VERSION 5.8 ;
BUSBITCHARS "[]" ;
DIVIDERCHAR "/" ;
UNITS
    DATABASE MICRONS 1000 ;
END UNITS

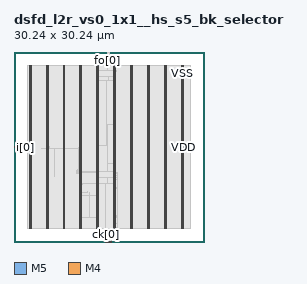
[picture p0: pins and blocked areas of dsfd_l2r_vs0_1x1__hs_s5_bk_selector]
MACRO dsfd_l2r_vs0_1x1__hs_s5_bk_selector
  FOREIGN dsfd_l2r_vs0_1x1__hs_s5_bk_selector 0 0 ;
  CLASS BLOCK ;
  SIZE 30.24 BY 30.24 ;
  PIN ck[0]
    DIRECTION INPUT ;
    USE SIGNAL ;
    PORT
      LAYER M5 ;
        RECT  14.64 0 14.664 0.084 ;
    END
  END ck[0]
  PIN cks[0]
    DIRECTION INPUT ;
    USE SIGNAL ;
    PORT
      LAYER M5 ;
        RECT  14.832 0 14.856 0.084 ;
    END
  END cks[0]
  PIN fo[0]
    DIRECTION OUTPUT ;
    USE SIGNAL ;
    PORT
      LAYER M5 ;
        RECT  14.928 30.156 14.952 30.24 ;
    END
  END fo[0]
  PIN i[0]
    DIRECTION INPUT ;
    USE SIGNAL ;
    PORT
      LAYER M4 ;
        RECT  0 15.072 0.084 15.096 ;
    END
  END i[0]
  PIN i[1]
    DIRECTION INPUT ;
    USE SIGNAL ;
    PORT
      LAYER M4 ;
        RECT  0 15.12 0.084 15.144 ;
    END
  END i[1]
  PIN od[0]
    DIRECTION OUTPUT ;
    USE SIGNAL ;
    PORT
      LAYER M5 ;
        RECT  15.12 30.156 15.144 30.24 ;
    END
  END od[0]
  PIN od[1]
    DIRECTION OUTPUT ;
    USE SIGNAL ;
    PORT
      LAYER M5 ;
        RECT  15.168 30.156 15.192 30.24 ;
    END
  END od[1]
  PIN od[2]
    DIRECTION OUTPUT ;
    USE SIGNAL ;
    PORT
      LAYER M5 ;
        RECT  15.216 30.156 15.24 30.24 ;
    END
  END od[2]
  PIN rs[0]
    DIRECTION INPUT ;
    USE SIGNAL ;
    PORT
      LAYER M5 ;
        RECT  15.024 0 15.048 0.084 ;
    END
  END rs[0]
  PIN rss[0]
    DIRECTION INPUT ;
    USE SIGNAL ;
    PORT
      LAYER M5 ;
        RECT  15.216 0 15.24 0.084 ;
    END
  END rss[0]
  PIN xf[0]
    DIRECTION INPUT ;
    USE SIGNAL ;
    PORT
      LAYER M5 ;
        RECT  15.408 0 15.432 0.084 ;
    END
  END xf[0]
  PIN xf[1]
    DIRECTION INPUT ;
    USE SIGNAL ;
    PORT
      LAYER M5 ;
        RECT  15.456 0 15.48 0.084 ;
    END
  END xf[1]
  PIN xf[2]
    DIRECTION INPUT ;
    USE SIGNAL ;
    PORT
      LAYER M5 ;
        RECT  15.504 0 15.528 0.084 ;
    END
  END xf[2]
  PIN xf[3]
    DIRECTION INPUT ;
    USE SIGNAL ;
    PORT
      LAYER M5 ;
        RECT  15.552 0 15.576 0.084 ;
    END
  END xf[3]
  PIN VDD
    DIRECTION INOUT ;
    USE POWER ;
    PORT
      LAYER M5 ;
        RECT  26.892 2.151 27.012 28.089 ;
        RECT  24.192 2.151 24.312 28.089 ;
        RECT  21.492 2.151 21.612 28.089 ;
        RECT  18.792 2.151 18.912 28.089 ;
        RECT  16.092 2.151 16.212 28.089 ;
        RECT  13.392 2.151 13.512 28.089 ;
        RECT  10.692 2.151 10.812 28.089 ;
        RECT  7.992 2.151 8.112 28.089 ;
        RECT  5.292 2.151 5.412 28.089 ;
        RECT  2.592 2.151 2.712 28.089 ;
    END
  END VDD
  PIN VSS
    DIRECTION INOUT ;
    USE GROUND ;
    PORT
      LAYER M5 ;
        RECT  26.7 2.137 26.82 28.103 ;
        RECT  24 2.137 24.12 28.103 ;
        RECT  21.3 2.137 21.42 28.103 ;
        RECT  18.6 2.137 18.72 28.103 ;
        RECT  15.9 2.137 16.02 28.103 ;
        RECT  13.2 2.137 13.32 28.103 ;
        RECT  10.5 2.137 10.62 28.103 ;
        RECT  7.8 2.137 7.92 28.103 ;
        RECT  5.1 2.137 5.22 28.103 ;
        RECT  2.4 2.137 2.52 28.103 ;
    END
  END VSS
  # OT_OBS_CLOSED layer=M5 d_um=1.536 added=11
  OBS
    LAYER RVTN ;
     RECT  2.16 2.16 28.08 2.295 ;
     RECT  2.16 2.565 28.08 2.835 ;
     RECT  2.16 3.105 28.08 3.375 ;
     RECT  2.16 3.645 28.08 3.915 ;
     RECT  2.16 4.185 28.08 4.455 ;
     RECT  2.16 4.725 28.08 4.995 ;
     RECT  2.16 5.265 28.08 5.535 ;
     RECT  2.16 5.805 28.08 6.075 ;
     RECT  2.16 6.345 28.08 6.615 ;
     RECT  2.16 6.885 28.08 7.155 ;
     RECT  2.16 7.425 28.08 7.695 ;
     RECT  2.16 7.965 28.08 8.235 ;
     RECT  2.16 8.505 28.08 8.775 ;
     RECT  2.16 9.045 28.08 9.315 ;
     RECT  2.16 9.585 28.08 9.855 ;
     RECT  2.16 10.125 28.08 10.395 ;
     RECT  2.16 10.665 28.08 10.935 ;
     RECT  2.16 11.205 28.08 11.475 ;
     RECT  2.16 11.745 28.08 12.015 ;
     RECT  2.16 12.285 28.08 12.555 ;
     RECT  2.16 12.825 28.08 13.095 ;
     RECT  2.16 13.365 28.08 13.635 ;
     RECT  2.16 13.905 28.08 14.175 ;
     RECT  2.16 14.445 28.08 14.715 ;
     RECT  2.16 14.985 28.08 15.255 ;
     RECT  2.16 15.525 28.08 15.795 ;
     RECT  2.16 16.065 28.08 16.335 ;
     RECT  2.16 16.605 28.08 16.875 ;
     RECT  2.16 17.145 28.08 17.415 ;
     RECT  2.16 17.685 28.08 17.955 ;
     RECT  2.16 18.225 28.08 18.495 ;
     RECT  2.16 18.765 28.08 19.035 ;
     RECT  2.16 19.305 28.08 19.575 ;
     RECT  2.16 19.845 28.08 20.115 ;
     RECT  2.16 20.385 28.08 20.655 ;
     RECT  2.16 20.925 28.08 21.195 ;
     RECT  2.16 21.465 28.08 21.735 ;
     RECT  2.16 22.005 28.08 22.275 ;
     RECT  2.16 22.545 28.08 22.815 ;
     RECT  2.16 23.085 28.08 23.355 ;
     RECT  2.16 23.625 28.08 23.895 ;
     RECT  2.16 24.165 28.08 24.435 ;
     RECT  2.16 24.705 28.08 24.975 ;
     RECT  2.16 25.245 28.08 25.515 ;
     RECT  2.16 25.785 28.08 26.055 ;
     RECT  2.16 26.325 28.08 26.595 ;
     RECT  2.16 26.865 28.08 27.135 ;
     RECT  2.16 27.405 28.08 27.675 ;
     RECT  2.16 27.945 28.08 28.08 ;
    LAYER RVTP ;
     RECT  2.16 2.295 28.08 2.565 ;
     RECT  2.16 2.835 28.08 3.105 ;
     RECT  2.16 3.375 28.08 3.645 ;
     RECT  2.16 3.915 28.08 4.185 ;
     RECT  2.16 4.455 28.08 4.725 ;
     RECT  2.16 4.995 28.08 5.265 ;
     RECT  2.16 5.535 28.08 5.805 ;
     RECT  2.16 6.075 28.08 6.345 ;
     RECT  2.16 6.615 28.08 6.885 ;
     RECT  2.16 7.155 28.08 7.425 ;
     RECT  2.16 7.695 28.08 7.965 ;
     RECT  2.16 8.235 28.08 8.505 ;
     RECT  2.16 8.775 28.08 9.045 ;
     RECT  2.16 9.315 28.08 9.585 ;
     RECT  2.16 9.855 28.08 10.125 ;
     RECT  2.16 10.395 28.08 10.665 ;
     RECT  2.16 10.935 28.08 11.205 ;
     RECT  2.16 11.475 28.08 11.745 ;
     RECT  2.16 12.015 28.08 12.285 ;
     RECT  2.16 12.555 28.08 12.825 ;
     RECT  2.16 13.095 28.08 13.365 ;
     RECT  2.16 13.635 28.08 13.905 ;
     RECT  2.16 14.175 28.08 14.445 ;
     RECT  2.16 14.715 28.08 14.985 ;
     RECT  2.16 15.255 28.08 15.525 ;
     RECT  2.16 15.795 28.08 16.065 ;
     RECT  2.16 16.335 28.08 16.605 ;
     RECT  2.16 16.875 28.08 17.145 ;
     RECT  2.16 17.415 28.08 17.685 ;
     RECT  2.16 17.955 28.08 18.225 ;
     RECT  2.16 18.495 28.08 18.765 ;
     RECT  2.16 19.035 28.08 19.305 ;
     RECT  2.16 19.575 28.08 19.845 ;
     RECT  2.16 20.115 28.08 20.385 ;
     RECT  2.16 20.655 28.08 20.925 ;
     RECT  2.16 21.195 28.08 21.465 ;
     RECT  2.16 21.735 28.08 22.005 ;
     RECT  2.16 22.275 28.08 22.545 ;
     RECT  2.16 22.815 28.08 23.085 ;
     RECT  2.16 23.355 28.08 23.625 ;
     RECT  2.16 23.895 28.08 24.165 ;
     RECT  2.16 24.435 28.08 24.705 ;
     RECT  2.16 24.975 28.08 25.245 ;
     RECT  2.16 25.515 28.08 25.785 ;
     RECT  2.16 26.055 28.08 26.325 ;
     RECT  2.16 26.595 28.08 26.865 ;
     RECT  2.16 27.135 28.08 27.405 ;
     RECT  2.16 27.675 28.08 27.945 ;
    LAYER M1 ;
     RECT  2.16 2.151 28.08 28.089 ;
    LAYER M2 ;
     RECT  2.16 2.151 28.08 28.089 ;
    LAYER M3 ;
     RECT  15.3 0.139 15.318 1.723 ;
     RECT  15.3 1.723 15.498 1.771 ;
     RECT  15.3 1.771 15.75 2.143 ;
     RECT  15.3 2.143 16.005 2.263 ;
     RECT  2.415 2.143 2.505 2.413 ;
     RECT  5.115 2.143 5.205 2.413 ;
     RECT  7.815 2.143 7.905 2.413 ;
     RECT  10.515 2.143 10.605 2.413 ;
     RECT  13.215 2.143 13.305 2.413 ;
     RECT  18.615 2.143 18.705 2.413 ;
     RECT  21.315 2.143 21.405 2.413 ;
     RECT  24.015 2.143 24.105 2.413 ;
     RECT  26.715 2.143 26.805 2.413 ;
     RECT  15.3 2.263 16.398 2.911 ;
     RECT  15.048 2.911 16.398 3.839 ;
     RECT  14.508 3.847 14.526 3.917 ;
     RECT  15.264 3.839 16.398 3.991 ;
     RECT  15.264 3.991 16.542 4.145 ;
     RECT  11.952 7.435 11.97 7.889 ;
     RECT  11.736 7.915 11.754 7.961 ;
     RECT  15.444 4.145 16.542 8.539 ;
     RECT  14.976 8.539 16.542 8.735 ;
     RECT  10.515 2.413 10.797 9.115 ;
     RECT  10.515 9.115 10.854 9.293 ;
     RECT  13.215 2.413 13.497 9.895 ;
     RECT  15.012 8.735 16.542 9.895 ;
     RECT  13.215 9.895 14.094 9.931 ;
     RECT  13.215 9.931 14.238 10.021 ;
     RECT  14.976 9.895 16.542 10.021 ;
     RECT  13.215 10.021 16.542 10.301 ;
     RECT  14.436 10.301 16.542 10.625 ;
     RECT  10.515 9.293 10.797 10.843 ;
     RECT  14.724 10.625 16.542 10.895 ;
     RECT  15.3 10.895 16.542 11.039 ;
     RECT  5.115 2.413 5.397 11.137 ;
     RECT  9.972 10.843 10.797 11.137 ;
     RECT  9.972 11.137 10.854 11.273 ;
     RECT  9.972 11.273 10.797 11.399 ;
     RECT  10.224 11.399 10.797 11.705 ;
     RECT  15.3 11.039 16.197 12.523 ;
     RECT  15.192 12.523 16.197 13.531 ;
     RECT  15.048 13.531 16.197 14.377 ;
     RECT  6.48 10.471 6.498 14.909 ;
     RECT  5.115 11.137 5.454 14.917 ;
     RECT  4.464 14.917 5.562 14.957 ;
     RECT  2.415 2.413 2.697 15.025 ;
     RECT  5.115 14.957 5.562 15.061 ;
     RECT  2.304 15.025 2.697 15.115 ;
     RECT  5.115 15.061 5.706 15.179 ;
     RECT  2.232 15.115 2.697 15.215 ;
     RECT  14.616 14.377 16.197 15.323 ;
     RECT  14.76 15.323 16.197 15.341 ;
     RECT  15.012 15.341 16.197 15.485 ;
     RECT  15.048 15.485 16.197 18.379 ;
     RECT  14.904 18.379 16.197 18.571 ;
     RECT  14.724 18.571 16.197 18.797 ;
     RECT  15.048 18.797 16.197 18.833 ;
     RECT  15.12 18.833 16.197 20.539 ;
     RECT  14.76 20.539 16.197 20.849 ;
     RECT  15.048 20.849 16.197 23.371 ;
     RECT  14.832 23.371 16.197 23.549 ;
     RECT  15.012 23.549 16.197 23.741 ;
     RECT  15.048 23.741 16.197 25.675 ;
     RECT  14.724 25.675 16.197 26.015 ;
     RECT  14.94 26.015 16.197 26.779 ;
     RECT  14.76 26.779 16.197 27.211 ;
     RECT  14.76 27.211 16.254 27.329 ;
     RECT  14.76 27.329 16.197 27.365 ;
     RECT  2.415 15.215 2.697 27.827 ;
     RECT  5.115 15.179 5.397 27.827 ;
     RECT  7.815 2.413 8.097 27.827 ;
     RECT  10.515 11.705 10.797 27.827 ;
     RECT  13.215 10.301 13.497 27.827 ;
     RECT  14.868 27.365 16.197 27.827 ;
     RECT  18.615 2.413 18.897 27.827 ;
     RECT  21.315 2.413 21.597 27.827 ;
     RECT  24.015 2.413 24.297 27.827 ;
     RECT  26.715 2.413 26.997 27.827 ;
     RECT  14.868 27.827 16.038 27.869 ;
     RECT  14.868 27.869 16.005 27.905 ;
     RECT  2.415 27.827 2.505 28.097 ;
     RECT  5.115 27.827 5.205 28.097 ;
     RECT  7.815 27.827 7.905 28.097 ;
     RECT  10.515 27.827 10.605 28.097 ;
     RECT  13.215 27.827 13.305 28.097 ;
     RECT  15.084 27.905 16.005 28.097 ;
     RECT  18.615 27.827 18.705 28.097 ;
     RECT  21.315 27.827 21.405 28.097 ;
     RECT  24.015 27.827 24.105 28.097 ;
     RECT  26.715 27.827 26.805 28.097 ;
     RECT  15.084 28.097 15.39 28.493 ;
     RECT  15.084 28.493 15.102 29.069 ;
    LAYER M4 ;
     RECT  0.06 15.072 2.408 15.144 ;
     RECT  2.408 2.148 2.512 28.092 ;
     RECT  2.512 2.418 2.704 27.822 ;
     RECT  4.453 14.928 5.108 14.952 ;
     RECT  5.108 2.148 5.212 28.092 ;
     RECT  5.212 2.418 5.404 27.822 ;
     RECT  5.404 14.928 7.808 14.952 ;
     RECT  7.808 2.148 7.912 28.092 ;
     RECT  7.912 2.418 8.104 27.822 ;
     RECT  9.961 10.848 10.172 10.872 ;
     RECT  10.357 7.92 10.508 7.944 ;
     RECT  10.357 9.408 10.508 9.432 ;
     RECT  10.172 10.848 10.508 11.592 ;
     RECT  8.104 14.928 10.508 14.952 ;
     RECT  10.508 2.148 10.612 28.092 ;
     RECT  10.612 2.418 10.804 27.822 ;
     RECT  10.804 9.12 10.865 9.288 ;
     RECT  10.804 7.92 11.765 7.944 ;
     RECT  11.941 7.44 12.025 7.464 ;
     RECT  11.941 3.888 13.208 3.912 ;
     RECT  10.865 9.264 13.208 9.288 ;
     RECT  10.804 11.136 13.208 11.16 ;
     RECT  13.208 2.148 13.312 28.092 ;
     RECT  13.312 2.418 13.504 27.822 ;
     RECT  13.504 10.272 14.243 11.16 ;
     RECT  14.243 10.272 14.465 10.296 ;
     RECT  13.504 9.264 14.675 9.288 ;
     RECT  14.713 18.768 14.725 18.792 ;
     RECT  14.713 25.68 14.797 25.704 ;
     RECT  14.725 15.312 14.812 15.336 ;
     RECT  14.749 20.544 14.867 20.568 ;
     RECT  14.749 26.784 14.885 26.808 ;
     RECT  14.885 26.784 14.924 27.336 ;
     RECT  14.725 18.384 14.933 18.792 ;
     RECT  14.821 23.376 14.957 23.4 ;
     RECT  15.073 29.04 15.109 29.064 ;
     RECT  15.109 28.464 15.173 29.064 ;
     RECT  15.173 28.416 15.203 29.064 ;
     RECT  15.203 28.416 15.401 28.488 ;
     RECT  15.289 0.144 15.491 0.168 ;
     RECT  15.397 1.728 15.493 1.752 ;
     RECT  15.493 1.728 15.509 1.8 ;
     RECT  15.509 1.776 15.533 1.8 ;
     RECT  15.533 1.776 15.761 1.896 ;
     RECT  13.504 3.888 15.908 3.912 ;
     RECT  14.965 8.544 15.908 8.568 ;
     RECT  15.181 12.528 15.908 12.552 ;
     RECT  14.933 18.768 15.908 18.792 ;
     RECT  14.917 20.688 15.908 20.856 ;
     RECT  14.957 23.376 15.908 23.736 ;
     RECT  14.924 26.256 15.908 27.336 ;
     RECT  15.908 2.148 16.012 28.092 ;
     RECT  16.012 2.418 16.204 27.822 ;
     RECT  18.608 2.148 18.712 28.092 ;
     RECT  18.712 2.418 18.904 27.822 ;
     RECT  21.308 2.148 21.412 28.092 ;
     RECT  21.412 2.418 21.604 27.822 ;
     RECT  24.008 2.148 24.112 28.092 ;
     RECT  24.112 2.418 24.304 27.822 ;
     RECT  26.708 2.148 26.812 28.092 ;
     RECT  26.812 2.418 27.004 27.822 ;
    LAYER M5 ;
     RECT  14.64 0.016 15.576 2.137 ;
     RECT  2.4 2.137 2.52 2.151 ;
     RECT  5.1 2.137 5.22 2.151 ;
     RECT  7.8 2.137 7.92 2.151 ;
     RECT  10.5 2.137 10.62 2.151 ;
     RECT  13.2 2.137 13.32 2.151 ;
     RECT  14.64 2.137 16.02 2.151 ;
     RECT  18.6 2.137 18.72 2.151 ;
     RECT  21.3 2.137 21.42 2.151 ;
     RECT  24 2.137 24.12 2.151 ;
     RECT  26.7 2.137 26.82 2.151 ;
     RECT  11.952 3.877 11.976 7.475 ;
     RECT  10.5 2.151 10.812 7.909 ;
     RECT  14.64 2.151 16.212 9.299 ;
     RECT  13.2 2.151 13.512 10.261 ;
     RECT  14.832 9.299 16.212 10.261 ;
     RECT  10.368 7.909 10.812 11.125 ;
     RECT  13.2 10.261 16.212 11.171 ;
     RECT  14.832 11.171 16.212 12.563 ;
     RECT  10.224 11.125 10.812 14.963 ;
     RECT  14.832 12.563 14.856 15.301 ;
     RECT  14.736 15.301 14.856 18.757 ;
     RECT  15.9 12.563 16.212 18.757 ;
     RECT  14.736 18.757 16.212 25.715 ;
     RECT  14.976 25.715 16.212 26.291 ;
     RECT  15.9 26.291 16.212 27.301 ;
     RECT  2.4 2.151 2.712 28.089 ;
     RECT  5.1 2.151 5.412 28.089 ;
     RECT  7.8 2.151 8.112 28.089 ;
     RECT  10.5 14.963 10.812 28.089 ;
     RECT  13.2 11.171 13.512 28.089 ;
     RECT  14.928 27.301 16.212 28.089 ;
     RECT  18.6 2.151 18.912 28.089 ;
     RECT  21.3 2.151 21.612 28.089 ;
     RECT  24 2.151 24.312 28.089 ;
     RECT  26.7 2.151 27.012 28.089 ;
     RECT  2.4 28.089 2.52 28.103 ;
     RECT  5.1 28.089 5.22 28.103 ;
     RECT  7.8 28.089 7.92 28.103 ;
     RECT  10.5 28.089 10.62 28.103 ;
     RECT  13.2 28.089 13.32 28.103 ;
     RECT  14.928 28.089 16.02 28.103 ;
     RECT  18.6 28.089 18.72 28.103 ;
     RECT  21.3 28.089 21.42 28.103 ;
     RECT  24 28.089 24.12 28.103 ;
     RECT  26.7 28.089 26.82 28.103 ;
     RECT  14.928 28.103 15.24 30.224 ;
     RECT  13.32 2.137 14.64 2.151 ;
     RECT  13.512 2.151 14.64 9.299 ;
     RECT  10.812 3.877 11.952 7.475 ;
     RECT  11.976 3.877 13.2 7.475 ;
     RECT  13.512 9.299 14.832 10.261 ;
     RECT  13.512 11.171 14.832 15.301 ;
     RECT  14.856 12.563 15.9 18.757 ;
     RECT  13.512 15.301 14.736 25.715 ;
     RECT  13.512 25.715 14.976 26.291 ;
     RECT  13.512 26.291 15.9 27.301 ;
     RECT  13.512 27.301 14.928 28.089 ;
  END
END dsfd_l2r_vs0_1x1__hs_s5_bk_selector
END LIBRARY
